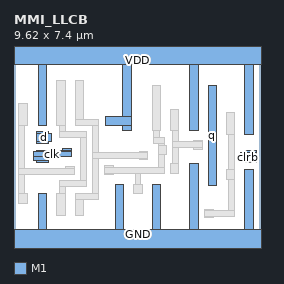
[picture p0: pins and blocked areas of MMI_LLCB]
MACRO MMI_LLCB
	CLASS CORE ;
	FOREIGN MMI_LLCB 0 0 ;
	SIZE 9.62 BY 7.4 ;
	SYMMETRY X Y ;
	SITE CORE1 ;
	PIN d
		DIRECTION input ;
		USE SIGNAL ;
		PORT
			LAYER M1 ;
			RECT 0.885 4.235 1.335 4.295 ;
			LAYER M1 ;
			RECT 0.885 3.895 1.475 4.235 ;
			LAYER M1 ;
			RECT 0.885 3.845 1.335 3.895 ;
		END
		AntennaGateArea 0.4968 ;
	END d
	PIN GND
		DIRECTION inout ;
		USE GROUND ;
		PORT
			LAYER M1 ;
			RECT 0.94 0.5 1.28 1.875 ;
			LAYER M1 ;
			RECT 3.935 0.5 4.275 2.25 ;
			LAYER M1 ;
			RECT 5.375 0.5 5.715 2.25 ;
			LAYER M1 ;
			RECT 6.84 0.5 7.18 3.06 ;
			LAYER M1 ;
			RECT 8.98 0.5 9.32 2.815 ;
			LAYER M1 ;
			RECT 0 -0.5 9.62 0.5 ;
		END
	END GND
	PIN q
		DIRECTION output ;
		USE SIGNAL ;
		PORT
			LAYER M1 ;
			RECT 7.56 2.22 7.9 6.095 ;
		END
		AntennaDiffArea 1.3248 ;
	END q
	PIN VDD
		DIRECTION inout ;
		USE POWER ;
		PORT
			LAYER M1 ;
			RECT 0 6.9 9.62 7.9 ;
			LAYER M1 ;
			RECT 0.94 4.535 1.28 6.9 ;
			LAYER M1 ;
			RECT 4.225 4.875 4.565 6.9 ;
			LAYER M1 ;
			RECT 3.57 4.535 4.565 4.875 ;
			LAYER M1 ;
			RECT 4.225 4.335 4.565 4.535 ;
			LAYER M1 ;
			RECT 6.84 4.335 7.18 6.9 ;
			LAYER M1 ;
			RECT 8.98 4.2 9.32 6.9 ;
		END
	END VDD
	PIN clk
		DIRECTION input ;
		USE CLOCK ;
		PORT
			LAYER M1 ;
			RECT 1.9 3.555 2.24 3.66 ;
			LAYER M1 ;
			RECT 0.885 3.51 2.24 3.555 ;
			LAYER M1 ;
			RECT 0.75 3.325 2.24 3.51 ;
			LAYER M1 ;
			RECT 0.75 3.17 1.335 3.325 ;
			LAYER M1 ;
			RECT 1.9 3.32 2.24 3.325 ;
			LAYER M1 ;
			RECT 0.885 3.105 1.335 3.17 ;
		END
		AntennaGateArea 0.6552 ;
	END clk
	PIN clrb
		DIRECTION input ;
		USE SIGNAL ;
		PORT
			LAYER M1 ;
			RECT 8.99 3.47 9.445 3.56 ;
			LAYER M1 ;
			RECT 8.83 3.13 9.445 3.47 ;
			LAYER M1 ;
			RECT 8.99 3.114 9.445 3.13 ;
		END
		AntennaGateArea 0.2484 ;
	END clrb
	OBS
		LAYER M1 ;
		RECT 0.18 4.535 0.52 5.375 ;
		LAYER M1 ;
		RECT 1.66 4.535 2 6.295 ;
		LAYER M1 ;
		RECT 2.38 4.765 2.72 6.295 ;
		LAYER M1 ;
		RECT 2.38 4.535 3.29 4.765 ;
		LAYER M1 ;
		RECT 0.18 2.85 0.41 4.535 ;
		LAYER M1 ;
		RECT 1.77 4.305 2 4.535 ;
		LAYER M1 ;
		RECT 1.77 4.075 2.83 4.305 ;
		LAYER M1 ;
		RECT 2.02 2.85 2.36 2.96 ;
		LAYER M1 ;
		RECT 0.18 2.62 2.36 2.85 ;
		LAYER M1 ;
		RECT 0.18 1.875 0.41 2.62 ;
		LAYER M1 ;
		RECT 2.6 2.39 2.83 4.075 ;
		LAYER M1 ;
		RECT 1.77 2.16 2.83 2.39 ;
		LAYER M1 ;
		RECT 3.06 3.47 3.29 4.535 ;
		LAYER M1 ;
		RECT 5.375 4.335 5.715 6.095 ;
		LAYER M1 ;
		RECT 6.08 4.335 6.42 5.175 ;
		LAYER M1 ;
		RECT 5.425 4.075 5.655 4.335 ;
		LAYER M1 ;
		RECT 5.425 3.845 5.845 4.075 ;
		LAYER M1 ;
		RECT 5.615 3.74 5.845 3.845 ;
		LAYER M1 ;
		RECT 6.19 3.91 6.42 4.335 ;
		LAYER M1 ;
		RECT 6.99 3.91 7.33 3.95 ;
		LAYER M1 ;
		RECT 4.875 3.47 5.215 3.535 ;
		LAYER M1 ;
		RECT 3.06 3.24 5.215 3.47 ;
		LAYER M1 ;
		RECT 1.77 1.875 2 2.16 ;
		LAYER M1 ;
		RECT 3.06 1.875 3.29 3.24 ;
		LAYER M1 ;
		RECT 4.875 3.195 5.215 3.24 ;
		LAYER M1 ;
		RECT 5.615 3.4 5.955 3.74 ;
		LAYER M1 ;
		RECT 6.19 3.68 7.33 3.91 ;
		LAYER M1 ;
		RECT 3.525 2.89 3.865 2.965 ;
		LAYER M1 ;
		RECT 5.615 2.89 5.845 3.4 ;
		LAYER M1 ;
		RECT 6.19 3.065 6.42 3.68 ;
		LAYER M1 ;
		RECT 6.99 3.61 7.33 3.68 ;
		LAYER M1 ;
		RECT 3.525 2.66 5.845 2.89 ;
		LAYER M1 ;
		RECT 6.08 2.685 6.42 3.065 ;
		LAYER M1 ;
		RECT 3.525 2.625 3.865 2.66 ;
		LAYER M1 ;
		RECT 4.715 2.25 4.945 2.66 ;
		LAYER M1 ;
		RECT 0.18 1.495 0.52 1.875 ;
		LAYER M1 ;
		RECT 1.66 1.035 2 1.875 ;
		LAYER M1 ;
		RECT 2.38 1.645 3.29 1.875 ;
		LAYER M1 ;
		RECT 2.38 1.035 2.72 1.645 ;
		LAYER M1 ;
		RECT 4.655 1.87 4.995 2.25 ;
		LAYER M1 ;
		RECT 8.26 4.2 8.6 5.04 ;
		LAYER M1 ;
		RECT 8.37 2.815 8.6 4.2 ;
		LAYER M1 ;
		RECT 8.26 2.435 8.6 2.815 ;
		LAYER M1 ;
		RECT 7.42 1.22 7.76 1.275 ;
		LAYER M1 ;
		RECT 8.37 1.22 8.6 2.435 ;
		LAYER M1 ;
		RECT 7.42 0.99 8.6 1.22 ;
		LAYER M1 ;
		RECT 7.42 0.935 7.76 0.99 ;
	END
END MMI_LLCB
